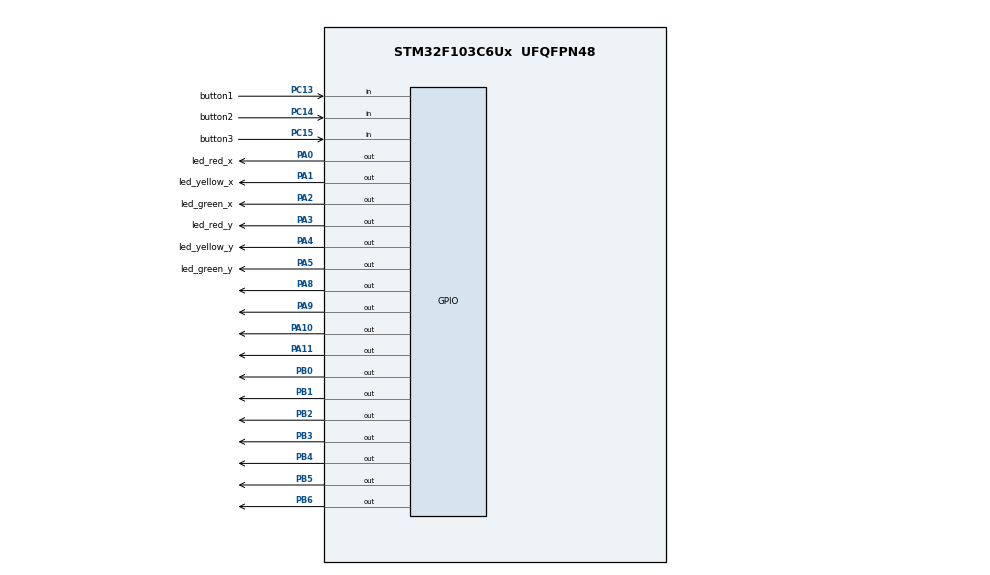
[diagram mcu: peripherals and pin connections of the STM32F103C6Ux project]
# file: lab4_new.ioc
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Mcu.Family=STM32F1
Mcu.Name=STM32F103C6Ux
Mcu.Package=UFQFPN48
NVIC.PriorityGroup=NVIC_PRIORITYGROUP_4
NVIC.TIM2_IRQn=true\:0\:0\:false\:false\:true\:true\:true
PA0-WKUP.GPIO_Label=led_red_x
PA0-WKUP.Signal=GPIO_Output
PA1.GPIO_Label=led_yellow_x
PA1.Signal=GPIO_Output
PA10.Signal=GPIO_Output
PA11.Signal=GPIO_Output
PA2.GPIO_Label=led_green_x
PA2.Signal=GPIO_Output
PA3.GPIO_Label=led_red_y
PA3.Signal=GPIO_Output
PA4.GPIO_Label=led_yellow_y
PA4.Signal=GPIO_Output
PA5.GPIO_Label=led_green_y
PA5.Signal=GPIO_Output
PA8.Signal=GPIO_Output
PA9.Signal=GPIO_Output
PB0.Signal=GPIO_Output
PB1.Signal=GPIO_Output
PB2.Signal=GPIO_Output
PB3.Signal=GPIO_Output
PB4.Signal=GPIO_Output
PB5.Signal=GPIO_Output
PB6.Signal=GPIO_Output
PC13-TAMPER-RTC.GPIO_Label=button1
PC13-TAMPER-RTC.GPIO_PuPd=GPIO_PULLUP
PC13-TAMPER-RTC.Signal=GPIO_Input
PC14-OSC32_IN.GPIO_Label=button2
PC14-OSC32_IN.GPIO_PuPd=GPIO_PULLUP
PC14-OSC32_IN.Signal=GPIO_Input
PC15-OSC32_OUT.GPIO_Label=button3
PC15-OSC32_OUT.GPIO_PuPd=GPIO_PULLUP
PC15-OSC32_OUT.Signal=GPIO_Input
ProjectManager.HeapSize=0x200
ProjectManager.StackSize=0x400
ProjectManager.TargetToolchain=STM32CubeIDE
RCC.APB1Freq_Value=8000000
RCC.APB2Freq_Value=8000000
TIM2.Period=9
TIM2.Prescaler=7999
VP_SYS_VS_ND.Mode=No_Debug
VP_TIM2_VS_ClockSourceINT.Mode=Internal
board=custom

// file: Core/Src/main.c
/* USER CODE BEGIN Header */
/**
  ******************************************************************************
  * @file           : main.c
  * @brief          : Main program body
  ******************************************************************************
  * @attention
  *
  * <h2><center>&copy; Copyright (c) 2024 STMicroelectronics.
  * All rights reserved.</center></h2>
  *
  * This software component is licensed by ST under BSD 3-Clause license,
  * the "License"; You may not use this file except in compliance with the
  * License. You may obtain a copy of the License at:
  *                        opensource.org/licenses/BSD-3-Clause
  *
  ******************************************************************************
  */
/* USER CODE END Header */
#include "main.h"

/* USER CODE BEGIN Includes */
#include"software_timer.h"
#include "global.h"
#include "fsm_automatic.h"
#include "scheduler.h"
/* USER CODE END Includes */

TIM_HandleTypeDef htim2;

void SystemClock_Config(void);
static void MX_GPIO_Init(void);
static void MX_TIM2_Init(void);

int main(void)
{

  /* MCU Configuration--------------------------------------------------------*/

  /* Reset of all peripherals, Initializes the Flash interface and the Systick. */
  HAL_Init();

  /* Configure the system clock */
  SystemClock_Config();

  /* Initialize all configured peripherals */
  MX_GPIO_Init();
  MX_TIM2_Init();
  /* USER CODE BEGIN 2 */
  HAL_TIM_Base_Start_IT(&htim2);
  /* USER CODE END 2 */

  /* Infinite loop */
  /* USER CODE BEGIN WHILE */
  	  status = INIT;
  	  SCH_Init();
  	  SCH_Add_Task(fsm_automatic_run, 1, 1);
  	  SCH_Add_Task(fsm_manual_run, 3, 1);
  while (1)
  {
	  SCH_Dispatch_Task();
//	  fsm_automatic_run();
//	  fsm_manual_run();

    /* USER CODE END WHILE */

  }
}

void SystemClock_Config(void)
{
  RCC_OscInitTypeDef RCC_OscInitStruct = {0};
  RCC_ClkInitTypeDef RCC_ClkInitStruct = {0};

  /** Initializes the RCC Oscillators according to the specified parameters
  * in the RCC_OscInitTypeDef structure.
  */
  RCC_OscInitStruct.OscillatorType = RCC_OSCILLATORTYPE_HSI;
  RCC_OscInitStruct.HSIState = RCC_HSI_ON;
  RCC_OscInitStruct.HSICalibrationValue = RCC_HSICALIBRATION_DEFAULT;
  RCC_OscInitStruct.PLL.PLLState = RCC_PLL_NONE;
  if (HAL_RCC_OscConfig(&RCC_OscInitStruct) != HAL_OK)
  {
    Error_Handler();
  }
  /** Initializes the CPU, AHB and APB buses clocks
  */
  RCC_ClkInitStruct.ClockType = RCC_CLOCKTYPE_HCLK|RCC_CLOCKTYPE_SYSCLK
                              |RCC_CLOCKTYPE_PCLK1|RCC_CLOCKTYPE_PCLK2;
  RCC_ClkInitStruct.SYSCLKSource = RCC_SYSCLKSOURCE_HSI;
  RCC_ClkInitStruct.AHBCLKDivider = RCC_SYSCLK_DIV1;
  RCC_ClkInitStruct.APB1CLKDivider = RCC_HCLK_DIV1;
  RCC_ClkInitStruct.APB2CLKDivider = RCC_HCLK_DIV1;

  if (HAL_RCC_ClockConfig(&RCC_ClkInitStruct, FLASH_LATENCY_0) != HAL_OK)
  {
    Error_Handler();
  }
}

static void MX_TIM2_Init(void)
{

  TIM_ClockConfigTypeDef sClockSourceConfig = {0};
  TIM_MasterConfigTypeDef sMasterConfig = {0};

  htim2.Instance = TIM2;
  htim2.Init.Prescaler = 7999;
  htim2.Init.CounterMode = TIM_COUNTERMODE_UP;
  htim2.Init.Period = 9;
  htim2.Init.ClockDivision = TIM_CLOCKDIVISION_DIV1;
  htim2.Init.AutoReloadPreload = TIM_AUTORELOAD_PRELOAD_DISABLE;
  if (HAL_TIM_Base_Init(&htim2) != HAL_OK)
  {
    Error_Handler();
  }
  sClockSourceConfig.ClockSource = TIM_CLOCKSOURCE_INTERNAL;
  if (HAL_TIM_ConfigClockSource(&htim2, &sClockSourceConfig) != HAL_OK)
  {
    Error_Handler();
  }
  sMasterConfig.MasterOutputTrigger = TIM_TRGO_RESET;
  sMasterConfig.MasterSlaveMode = TIM_MASTERSLAVEMODE_DISABLE;
  if (HAL_TIMEx_MasterConfigSynchronization(&htim2, &sMasterConfig) != HAL_OK)
  {
    Error_Handler();
  }

}

static void MX_GPIO_Init(void)
{
  GPIO_InitTypeDef GPIO_InitStruct = {0};

  /* GPIO Ports Clock Enable */
  __HAL_RCC_GPIOC_CLK_ENABLE();
  __HAL_RCC_GPIOA_CLK_ENABLE();
  __HAL_RCC_GPIOB_CLK_ENABLE();

  /*Configure GPIO pin Output Level */
  HAL_GPIO_WritePin(GPIOA, led_red_x_Pin|led_yellow_x_Pin|led_green_x_Pin|led_red_y_Pin
                          |led_yellow_y_Pin|led_green_y_Pin|GPIO_PIN_6|GPIO_PIN_8
                          |GPIO_PIN_9|GPIO_PIN_10|GPIO_PIN_11, GPIO_PIN_RESET);

  /*Configure GPIO pin Output Level */
  HAL_GPIO_WritePin(GPIOB, GPIO_PIN_0|GPIO_PIN_1|GPIO_PIN_2|GPIO_PIN_10
                          |GPIO_PIN_11|GPIO_PIN_12|GPIO_PIN_13|GPIO_PIN_3
                          |GPIO_PIN_4|GPIO_PIN_5|GPIO_PIN_6|GPIO_PIN_7
                          |GPIO_PIN_8|GPIO_PIN_9, GPIO_PIN_RESET);

  /*Configure GPIO pins : button1_Pin button2_Pin button3_Pin */
  GPIO_InitStruct.Pin = button1_Pin|button2_Pin|button3_Pin;
  GPIO_InitStruct.Mode = GPIO_MODE_INPUT;
  GPIO_InitStruct.Pull = GPIO_PULLUP;
  HAL_GPIO_Init(GPIOC, &GPIO_InitStruct);

  /*Configure GPIO pins : led_red_x_Pin led_yellow_x_Pin led_green_x_Pin led_red_y_Pin
                           led_yellow_y_Pin led_green_y_Pin PA6 PA8
                           PA9 PA10 PA11 */
  GPIO_InitStruct.Pin = led_red_x_Pin|led_yellow_x_Pin|led_green_x_Pin|led_red_y_Pin
                          |led_yellow_y_Pin|led_green_y_Pin|GPIO_PIN_6|GPIO_PIN_8
                          |GPIO_PIN_9|GPIO_PIN_10|GPIO_PIN_11;
  GPIO_InitStruct.Mode = GPIO_MODE_OUTPUT_PP;
  GPIO_InitStruct.Pull = GPIO_NOPULL;
  GPIO_InitStruct.Speed = GPIO_SPEED_FREQ_LOW;
  HAL_GPIO_Init(GPIOA, &GPIO_InitStruct);

  /*Configure GPIO pins : PB0 PB1 PB2 PB10
                           PB11 PB12 PB13 PB3
                           PB4 PB5 PB6 PB7
                           PB8 PB9 */
  GPIO_InitStruct.Pin = GPIO_PIN_0|GPIO_PIN_1|GPIO_PIN_2|GPIO_PIN_10
                          |GPIO_PIN_11|GPIO_PIN_12|GPIO_PIN_13|GPIO_PIN_3
                          |GPIO_PIN_4|GPIO_PIN_5|GPIO_PIN_6|GPIO_PIN_7
                          |GPIO_PIN_8|GPIO_PIN_9;
  GPIO_InitStruct.Mode = GPIO_MODE_OUTPUT_PP;
  GPIO_InitStruct.Pull = GPIO_NOPULL;
  GPIO_InitStruct.Speed = GPIO_SPEED_FREQ_LOW;
  HAL_GPIO_Init(GPIOB, &GPIO_InitStruct);

}

/* USER CODE BEGIN 4 */
void HAL_TIM_PeriodElapsedCallback(TIM_HandleTypeDef *htim)
{
	timer_run();
	getKeyInput();
	scanLedBuffer();
	SCH_Update();
}
/* USER CODE END 4 */

void Error_Handler(void)
{
  __disable_irq();
  while (1)
  {
  }
}

/************************ (C) COPYRIGHT STMicroelectronics *****END OF FILE****/
